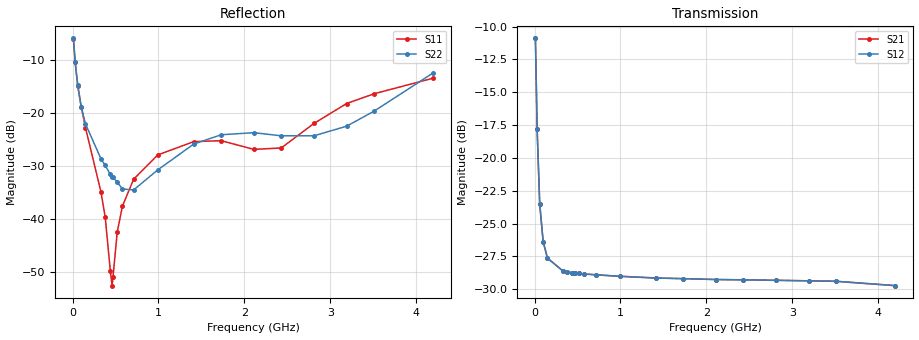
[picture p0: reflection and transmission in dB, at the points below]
! Integrated Device Technology
! Corporate Headquarters
! 6024 Silver Creek Valley Road
! San Jose, CA 95138  USA
! Phone:  1-408-284-8200
! Toll Free:  1-800-223-1366
! Webpage:  http://www.idt.com/
! Timing and RF Division
! 515 Groton Road, Suite 102
! Westford, MA 01886-6024
! Device:  F1950
! Description: 7-bit 0.25 dB Digital Step Attenuator
! Frequency:  150.0 -  4000.00 MHz
! Package:  4x4 mm Thin QFN Plastic Package: 24 pin
! Ports:  2 RF, 12 DC
!  Pin  1  = D0
!  Pin  2  = VDD
!  Pin  3  = Vmode
!  Pin  4  = GND
!  Pin  5  = RF1  =  Port 1
!  Pin  6  = GND
!  Pin  7  = GND
!  Pin  8  = GND
!  Pin  9  = GND
!  Pin 10  = GND
!  Pin 11  = GND
!  Pin 12  = GND
!  Pin 13  = GND
!  Pin 14  = RF2  =  Port 2
!  Pin 15  = GND
!  Pin 16  = LE
!  Pin 17  = CLK
!  Pin 18  = DATE
!  Pin 19  = D6
!  Pin 20  = D5
!  Pin 21  = D4
!  Pin 22  = D3
!  Pin 23  = D2
!  Pin 24  = D1
! State:  112
! Atten State:  28.00 dB
! Voltage:  +5.00 Volts
! Current:  Not Measured mA
! Data:  The device was measured on a the F195X evaluation board which has
!  individual transmission lines to the RF pins.  Data was collected
!  using a calibrated network analyzer.  The evaluation board was
!  de-embedded using a TRL calibration technique.
!  The reference plane is the edge of the package pin.
! Misc:  Board 2019
!  Action Tracker AT0250
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# GHz S dB R 50
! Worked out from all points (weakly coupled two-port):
!   420 points, 10 MHz to 4.2 GHz, reference 50 ohm
!   highest |S21| = -10.90 dB at 10 MHz (marker M1); lowest = -29.7 dB at 4.2 GHz (marker M2)
!   lowest |S11| = -52.6 dB at 460 MHz (marker M3), VSWR 1.00, Z = 49.8 - j0.0737 ohm
!   |S11| at or under -10 dB: 27.72 MHz to end of sweep
!   |S22| runs from -34.9 to -6.0 dB; largest |S21 - S12| = 8.3e-05
!   S11 on the Smith chart (normalised r, x): 10 MHz: 2.03, -1.28; 30 MHz: 1.26, -0.66; 60 MHz: 1.10, -0.37; 330 MHz: 1.01, -0.03; 4.2 GHz: 0.68, +0.17
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0.01  -6.04 -28.3  -10.90 -38.4  -10.90 -38.4  -5.98 -29.3
0.03  -10.47 -52.2  -17.82 -61.4  -17.82 -61.4  -10.41 -53.6
0.06  -14.96 -64.5  -23.52 -55.2  -23.51 -55.2  -14.75 -66.0
0.1  -18.84 -71.1  -26.38 -41.8  -26.37 -41.7  -18.84 -71.5
0.15  -22.81 -73.2  -27.63 -31.2  -27.63 -31.2  -22.10 -75.8
0.33  -34.92 -73.9  -28.61 -17.9  -28.61 -17.9  -28.69 -85.8
0.38  -39.71 -75.1  -28.68 -16.7  -28.68 -16.7  -29.95 -88.1
0.44  -49.92 -110.1  -28.75 -15.6  -28.75 -15.6  -31.64 -94.0
0.46  -52.63 -161.5  -28.76 -15.3  -28.76 -15.3  -32.04 -97.4
0.47  -51.07 172.2  -28.77 -15.2  -28.77 -15.2  -32.18 -99.1
0.52  -42.50 143.6  -28.80 -14.8  -28.80 -14.8  -33.11 -104.0
0.58  -37.64 137.2  -28.84 -14.5  -28.84 -14.5  -34.38 -116.8
0.71  -32.57 138.9  -28.90 -14.3  -28.90 -14.3  -34.58 -141.9
0.99  -27.98 147.5  -29.01 -15.1  -29.02 -15.1  -30.81 179.1
1.41  -25.46 162.6  -29.14 -17.3  -29.15 -17.3  -25.92 160.1
1.73  -25.28 167.8  -29.20 -19.2  -29.19 -19.2  -24.16 151.8
2.11  -26.92 157.4  -29.26 -22.3  -29.26 -22.4  -23.77 141.9
2.43  -26.65 126.1  -29.29 -24.4  -29.28 -24.4  -24.36 131.1
2.81  -22.03 105.3  -29.32 -27.6  -29.32 -27.6  -24.36 115.8
3.19  -18.27 108.6  -29.36 -30.7  -29.36 -30.7  -22.55 110.2
3.51  -16.43 117.4  -29.40 -33.0  -29.39 -33.0  -19.71 113.1
4.2  -13.48 145.6  -29.73 -35.7  -29.72 -35.8  -12.47 127.1
